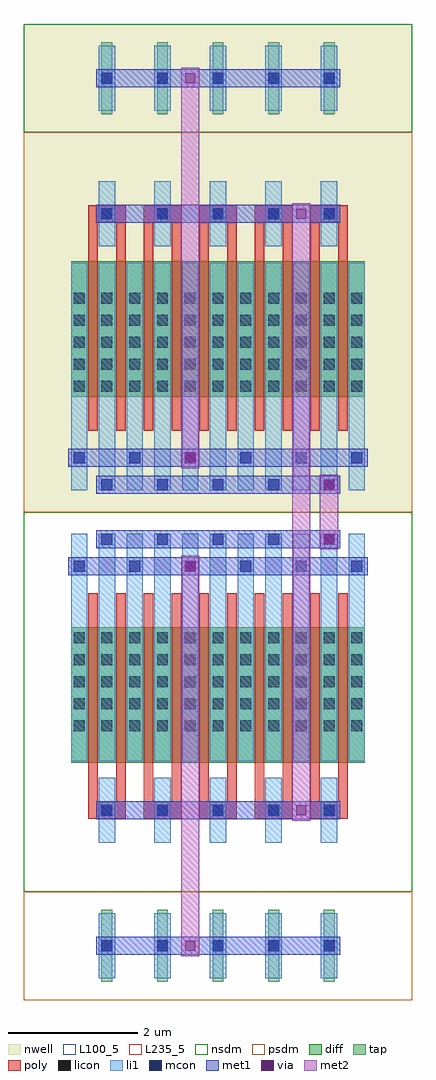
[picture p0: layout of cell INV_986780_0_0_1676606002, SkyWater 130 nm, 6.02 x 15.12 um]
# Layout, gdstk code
from math import pi, radians
import gdstk
lib = gdstk.Library(unit=1e-6, precision=1e-09)
def R(c, l, rs):  # rectangles x0, y0, x1, y1
    for r in rs: c.add(gdstk.rectangle(r[:2], r[2:], *l))
def A(c, l, x, y, w, h, nx, ny, dx, dy):  # array of equal rectangles
    R(c, l, [(x+i*dx, y+j*dy, x+i*dx+w, y+j*dy+h) for i in range(nx) for j in range(ny)])
def P(c, l, *ps):  # polygons
    for p in ps: c.add(gdstk.Polygon(p, *l))
nwell = (64, 20)
diff = (65, 20)
tap = (65, 44)
poly = (66, 20)
licon = (66, 44)
li1 = (67, 20)
mcon = (67, 44)
met1 = (68, 20)
via = (68, 44)
met2 = (69, 20)
nsdm = (93, 44)
psdm = (94, 20)
L100_5 = (100, 5)
L235_5 = (235, 5)

nmos_s_97854001_x5_y1_16 = lib.new_cell('NMOS_S_97854001_X5_Y1_1676606000_1676606002')
R(nmos_s_97854001_x5_y1_16, diff, [(0.735,1.785,5.285,3.885)])
A(nmos_s_97854001_x5_y1_16, tap, 1.205, 6.16, 0.17, 1.12, 5, 1, 0.86, 0)
A(nmos_s_97854001_x5_y1_16, poly, 1, 1.26, 0.15, 3.36, 10, 1, 0.43, 0)
A(nmos_s_97854001_x5_y1_16, poly, 1, 4.485, 0.58, 0.27, 5, 1, 0.86, 0)
A(nmos_s_97854001_x5_y1_16, licon, 0.775, 1.865, 0.17, 0.17, 3, 5, 0.43, 0.34)
A(nmos_s_97854001_x5_y1_16, licon, 1.635, 1.865, 0.17, 0.17, 3, 5, 0.43, 0.34)
A(nmos_s_97854001_x5_y1_16, licon, 2.495, 1.865, 0.17, 0.17, 3, 5, 0.43, 0.34)
A(nmos_s_97854001_x5_y1_16, licon, 3.355, 1.865, 0.17, 0.17, 3, 5, 0.43, 0.34)
A(nmos_s_97854001_x5_y1_16, licon, 4.215, 1.865, 0.17, 0.17, 3, 5, 0.43, 0.34)
A(nmos_s_97854001_x5_y1_16, licon, 1.205, 4.535, 0.17, 0.17, 5, 2, 0.86, 2.1)
A(nmos_s_97854001_x5_y1_16, li1, 0.735, 0.335, 0.25, 3.53, 11, 1, 0.43, 0)
A(nmos_s_97854001_x5_y1_16, li1, 1.165, 4.115, 0.25, 1.01, 5, 2, 0.86, 2.1)
A(nmos_s_97854001_x5_y1_16, mcon, 1.205, 0.335, 0.17, 0.17, 5, 2, 0.86, 4.2)
A(nmos_s_97854001_x5_y1_16, mcon, 0.775, 0.755, 0.17, 0.17, 6, 1, 0.86, 0)
A(nmos_s_97854001_x5_y1_16, mcon, 1.205, 6.635, 0.17, 0.17, 5, 1, 0.86, 0)
R(nmos_s_97854001_x5_y1_16, met1, [(1.12,0.28,4.9,0.56), (0.69,0.7,5.33,0.98), (1.12,4.48,4.9,4.76), (1.12,6.58,4.9,6.86)])
R(nmos_s_97854001_x5_y1_16, via, [(3.365,0.765,3.515,0.915), (3.365,6.645,3.515,6.795)])
R(nmos_s_97854001_x5_y1_16, met2, [(3.3,0.68,3.58,6.88)])
R(nmos_s_97854001_x5_y1_16, nsdm, [(0,0,6.02,5.88)])
R(nmos_s_97854001_x5_y1_16, psdm, [(0,5.88,6.02,7.56)])
R(nmos_s_97854001_x5_y1_16, L100_5, [(0,0,6.02,7.56)])

pmos_s_86637345_x5_y1_16 = lib.new_cell('PMOS_S_86637345_X5_Y1_1676606001_1676606002')
R(pmos_s_86637345_x5_y1_16, nwell, [(0,0,6.02,7.56)])
R(pmos_s_86637345_x5_y1_16, diff, [(0.735,1.785,5.285,3.885)])
A(pmos_s_86637345_x5_y1_16, tap, 1.205, 6.16, 0.17, 1.12, 5, 1, 0.86, 0)
A(pmos_s_86637345_x5_y1_16, poly, 1, 1.26, 0.15, 3.36, 10, 1, 0.43, 0)
A(pmos_s_86637345_x5_y1_16, poly, 1, 4.485, 0.58, 0.27, 5, 1, 0.86, 0)
A(pmos_s_86637345_x5_y1_16, licon, 0.775, 1.865, 0.17, 0.17, 3, 5, 0.43, 0.34)
A(pmos_s_86637345_x5_y1_16, licon, 1.635, 1.865, 0.17, 0.17, 3, 5, 0.43, 0.34)
A(pmos_s_86637345_x5_y1_16, licon, 2.495, 1.865, 0.17, 0.17, 3, 5, 0.43, 0.34)
A(pmos_s_86637345_x5_y1_16, licon, 3.355, 1.865, 0.17, 0.17, 3, 5, 0.43, 0.34)
A(pmos_s_86637345_x5_y1_16, licon, 4.215, 1.865, 0.17, 0.17, 3, 5, 0.43, 0.34)
A(pmos_s_86637345_x5_y1_16, licon, 1.205, 4.535, 0.17, 0.17, 5, 2, 0.86, 2.1)
A(pmos_s_86637345_x5_y1_16, li1, 0.735, 0.335, 0.25, 3.53, 11, 1, 0.43, 0)
A(pmos_s_86637345_x5_y1_16, li1, 1.165, 4.115, 0.25, 1.01, 5, 2, 0.86, 2.1)
A(pmos_s_86637345_x5_y1_16, mcon, 1.205, 0.335, 0.17, 0.17, 5, 2, 0.86, 4.2)
A(pmos_s_86637345_x5_y1_16, mcon, 0.775, 0.755, 0.17, 0.17, 6, 1, 0.86, 0)
A(pmos_s_86637345_x5_y1_16, mcon, 1.205, 6.635, 0.17, 0.17, 5, 1, 0.86, 0)
R(pmos_s_86637345_x5_y1_16, met1, [(1.12,0.28,4.9,0.56), (0.69,0.7,5.33,0.98), (1.12,4.48,4.9,4.76), (1.12,6.58,4.9,6.86)])
R(pmos_s_86637345_x5_y1_16, via, [(3.365,0.765,3.515,0.915), (3.365,6.645,3.515,6.795)])
R(pmos_s_86637345_x5_y1_16, met2, [(3.3,0.68,3.58,6.88)])
R(pmos_s_86637345_x5_y1_16, nsdm, [(0,5.88,6.02,7.56)])
R(pmos_s_86637345_x5_y1_16, psdm, [(0,0,6.02,5.88)])
R(pmos_s_86637345_x5_y1_16, L100_5, [(0,0,6.02,7.56)])

inv_986780_0_0_167660600 = lib.new_cell('INV_986780_0_0_1676606002')
R(inv_986780_0_0_167660600, met1, [(4.14,2.8,4.46,3.08), (4.14,2.8,4.46,3.08), (4.57,7,4.89,7.28), (4.57,7,4.89,7.28), (4.57,7.84,4.89,8.12), (4.57,7.84,4.89,8.12), (4.14,12.04,4.46,12.32), (4.14,12.04,4.46,12.32)])
P(inv_986780_0_0_167660600, met1, [(0,0),(0,0),(0,0),(0,0)],
  [(0,0),(0,0),(0,0),(0,0)],
  [(0,0),(0,0),(0,0),(0,0)],
  [(0,0),(0,0),(0,0),(0,0)])
R(inv_986780_0_0_167660600, via, [(4.225,2.865,4.375,3.015), (4.225,2.865,4.375,3.015), (4.655,7.065,4.805,7.215), (4.655,7.065,4.805,7.215), (4.655,7.905,4.805,8.055), (4.655,7.905,4.805,8.055), (4.225,12.105,4.375,12.255), (4.225,12.105,4.375,12.255)])
R(inv_986780_0_0_167660600, met2, [(4.16,2.78,4.44,3.1), (4.16,2.78,4.44,3.1), (4.16,2.94,4.44,12.18), (4.59,6.98,4.87,7.3), (4.59,6.98,4.87,7.3), (4.59,7.14,4.87,7.98), (4.59,7.82,4.87,8.14), (4.59,7.82,4.87,8.14), (4.16,12.02,4.44,12.34), (4.16,12.02,4.44,12.34)])
P(inv_986780_0_0_167660600, met2, [(0,0),(0,0),(0,0),(0,0)],
  [(0,0),(0,0),(0,0),(0,0)])
R(inv_986780_0_0_167660600, L235_5, [(0,0,6.02,15.12)])
inv_986780_0_0_167660600.add(gdstk.Reference(nmos_s_97854001_x5_y1_16, (6.02,7.56), rotation=pi))
inv_986780_0_0_167660600.add(gdstk.Reference(pmos_s_86637345_x5_y1_16, (6.02,7.56), rotation=pi, x_reflection=True))

lib.write_gds('INV_986780_0_0_1676606002.gds')
